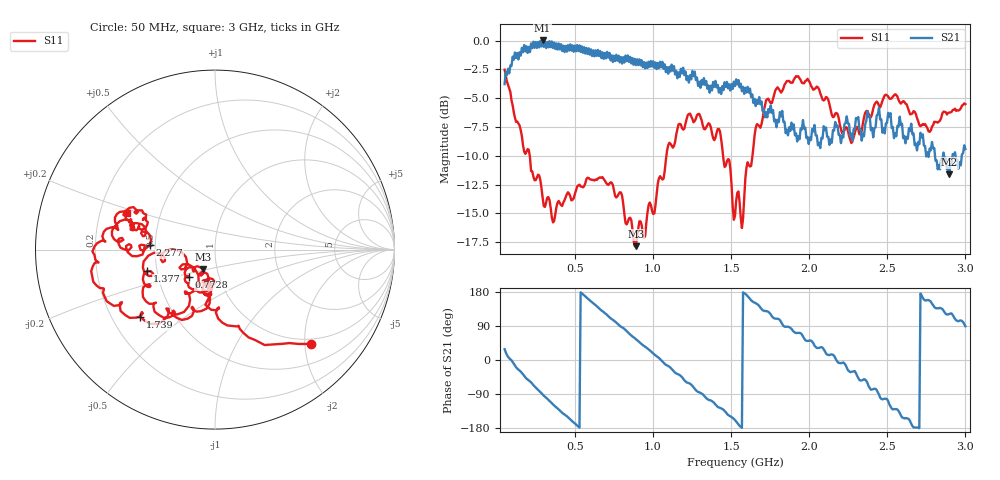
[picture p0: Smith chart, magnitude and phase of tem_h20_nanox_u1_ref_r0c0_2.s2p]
! nanovna_capture.py 2026-10-26T21:05:55+0900
! NanoVNA-F_V2 fw 0.6.0 SN 4A3639384505514B
! cal: load open short thru cal'ed  over 50000000-3000000000 Hz, 201 points
! points 401, avg 4
! TEM h=20, genuine Nano X, flat back down, 0 deg, centred, placement 2
# HZ S RI R 50
! S12 and S22 are not measured (written as 0)
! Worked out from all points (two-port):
!   401 points, 50 MHz to 3 GHz, reference 50 ohm
!   highest |S21| = 0.02 dB at 293.4 MHz (marker M1); lowest = -11.6 dB at 2.897 GHz (marker M2)
!   |S21| within 3 dB of the highest: 65 MHz to 1.153 GHz (1.088 GHz wide, 179 % of centre); 1.173 GHz to 1.2 GHz (27.62 MHz wide, 2.33 % of centre) (the widest 2 of 7)
!   lowest |S11| = -17.8 dB at 890.8 MHz (marker M3), VSWR 1.29, Z = 42.7 - j9.41 ohm
!   |S11| at or under -10 dB: 210.9 MHz to 1.086 GHz (874.9 MHz wide, 135 % of centre); 1.449 GHz to 1.637 GHz (188 MHz wide, 12.2 % of centre)
!   S12 and S22 are empty: the file has one direction only
!   S11 on the Smith chart (normalised r, x): 50 MHz: 0.89, -2.13; 772.8 MHz: 0.72, -0.23; 1.377 GHz: 0.44, -0.12; 1.739 GHz: 0.32, -0.35; 2.277 GHz: 0.47, +0.03; 3 GHz: 0.32, +0.18
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5e7  0.5327 -0.5254  0.5693 0.3093  0 0  0 0
1.01625e8  0.1868 -0.489  0.849 -0.0802  0 0  0 0
1.60625e8  0.0178 -0.3843  0.7704 -0.5234  0 0  0 0
2.93375e8  -0.0637 -0.1985  -0.0154 -1.002  0 0  0 0
4.11375e8  -0.0228 -0.1918  -0.7019 -0.6633  0 0  0 0
5.44125e8  -0.0653 -0.223  -0.9433 0.066  0 0  0 0
6.62125e8  -0.1313 -0.2187  -0.6208 0.6533  0 0  0 0
7.7275e8  -0.1439 -0.1544  -0.0864 0.8152  0 0  0 0
8.9075e8  -0.0682 -0.1085  0.4484 0.6422  0 0  0 0
1.03825e9  -0.0425 -0.2494  0.7561 0.0703  0 0  0 0
1.207875e9  -0.235 -0.3677  0.4073 -0.612  0 0  0 0
1.3775e9  -0.3793 -0.119  -0.1933 -0.5767  0 0  0 0
1.525e9  -0.1543 -0.0793  -0.591 -0.2329  0 0  0 0
1.635625e9  -0.1387 -0.279  -0.5303 0.2466  0 0  0 0
1.738875e9  -0.4166 -0.3739  -0.304 0.4029  0 0  0 0
1.92325e9  -0.6833 -0.1524  0.1161 0.3462  0 0  0 0
2.019125e9  -0.6234 0.0505  0.2737 0.3105  0 0  0 0
2.27725e9  -0.3641 0.0251  0.3185 -0.1852  0 0  0 0
2.51325e9  -0.5449 0.1321  -0.2136 -0.4168  0 0  0 0
2.653375e9  -0.4359 0.2013  -0.4272 -0.0881  0 0  0 0
2.89675e9  -0.4623 0.1538  -0.1377 0.224  0 0  0 0
3e9  -0.49 0.2023  0.00526 0.3384  0 0  0 0
